VERSION 5.7 ;
  NOWIREEXTENSIONATPIN ON ;
  DIVIDERCHAR "/" ;
  BUSBITCHARS "[]" ;
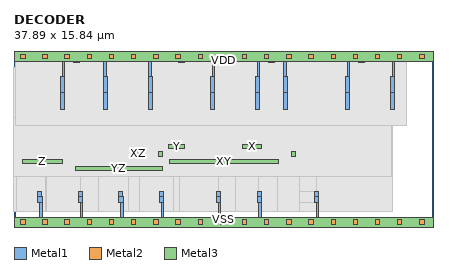
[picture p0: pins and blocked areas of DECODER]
MACRO DECODER
  CLASS BLOCK ;
  FOREIGN DECODER ;
  ORIGIN 1.000 0.000 ;
  SIZE 37.890 BY 15.840 ;
  PIN VSS
    DIRECTION INOUT ;
    USE GROUND ;
    PORT
      LAYER Metal1 ;
        RECT 1.140 2.730 1.500 3.230 ;
        RECT 4.800 2.730 5.160 3.230 ;
        RECT 8.460 2.730 8.820 3.230 ;
        RECT 12.120 2.730 12.480 3.230 ;
        RECT 17.280 2.730 17.640 3.230 ;
        RECT 20.940 2.730 21.300 3.230 ;
        RECT 26.100 2.730 26.460 3.230 ;
        RECT 1.140 2.230 1.530 2.730 ;
        RECT 4.800 2.230 5.190 2.730 ;
        RECT 8.460 2.230 8.850 2.730 ;
        RECT 12.120 2.230 12.510 2.730 ;
        RECT 17.280 2.230 17.670 2.730 ;
        RECT 20.940 2.230 21.330 2.730 ;
        RECT 26.100 2.230 26.490 2.730 ;
        RECT 1.300 0.900 1.530 2.230 ;
        RECT 4.960 0.900 5.190 2.230 ;
        RECT 8.620 0.900 8.850 2.230 ;
        RECT 12.280 0.900 12.510 2.230 ;
        RECT 17.440 0.900 17.670 2.230 ;
        RECT 21.100 0.900 21.330 2.230 ;
        RECT 26.260 0.900 26.490 2.230 ;
        RECT -1.000 0.000 36.890 0.900 ;
      LAYER Metal2 ;
        RECT -0.400 0.250 0.000 0.650 ;
        RECT 1.600 0.250 2.000 0.650 ;
        RECT 3.600 0.250 4.000 0.650 ;
        RECT 5.600 0.250 6.000 0.650 ;
        RECT 7.600 0.250 8.000 0.650 ;
        RECT 9.600 0.250 10.000 0.650 ;
        RECT 11.600 0.250 12.000 0.650 ;
        RECT 13.600 0.250 14.000 0.650 ;
        RECT 15.600 0.250 16.000 0.650 ;
        RECT 17.600 0.250 18.000 0.650 ;
        RECT 19.600 0.250 20.000 0.650 ;
        RECT 21.600 0.250 22.000 0.650 ;
        RECT 23.600 0.250 24.000 0.650 ;
        RECT 25.600 0.250 26.000 0.650 ;
        RECT 27.600 0.250 28.000 0.650 ;
        RECT 29.600 0.250 30.000 0.650 ;
        RECT 31.600 0.250 32.000 0.650 ;
        RECT 33.600 0.250 34.000 0.650 ;
        RECT 35.600 0.250 36.000 0.650 ;
      LAYER Metal3 ;
        RECT -1.000 0.000 36.890 0.900 ;
    END
  END VSS
  PIN VDD
    DIRECTION INOUT ;
    USE POWER ;
    PORT
      LAYER Metal1 ;
        RECT -1.000 14.940 36.890 15.840 ;
        RECT 3.360 13.610 3.590 14.940 ;
        RECT 4.410 14.840 4.890 14.940 ;
        RECT 3.200 12.110 3.590 13.610 ;
        RECT 7.080 13.610 7.310 14.940 ;
        RECT 11.140 13.610 11.370 14.940 ;
        RECT 13.880 14.840 14.360 14.940 ;
        RECT 16.890 13.610 17.120 14.940 ;
        RECT 20.950 13.610 21.180 14.940 ;
        RECT 22.000 14.840 22.480 14.940 ;
        RECT 7.080 12.110 7.470 13.610 ;
        RECT 11.140 12.110 11.530 13.610 ;
        RECT 3.200 10.610 3.560 12.110 ;
        RECT 7.110 10.610 7.470 12.110 ;
        RECT 11.170 10.610 11.530 12.110 ;
        RECT 16.730 12.110 17.120 13.610 ;
        RECT 20.790 12.110 21.180 13.610 ;
        RECT 23.320 13.610 23.550 14.940 ;
        RECT 29.070 13.610 29.300 14.940 ;
        RECT 30.120 14.840 30.600 14.940 ;
        RECT 33.130 13.610 33.360 14.940 ;
        RECT 23.320 12.110 23.710 13.610 ;
        RECT 16.730 10.610 17.090 12.110 ;
        RECT 20.790 10.610 21.150 12.110 ;
        RECT 23.350 10.610 23.710 12.110 ;
        RECT 28.910 12.110 29.300 13.610 ;
        RECT 32.970 12.110 33.360 13.610 ;
        RECT 28.910 10.610 29.270 12.110 ;
        RECT 32.970 10.610 33.330 12.110 ;
      LAYER Metal2 ;
        RECT -0.400 15.190 0.000 15.590 ;
        RECT 1.600 15.190 2.000 15.590 ;
        RECT 3.600 15.190 4.000 15.590 ;
        RECT 5.600 15.190 6.000 15.590 ;
        RECT 7.600 15.190 8.000 15.590 ;
        RECT 9.600 15.190 10.000 15.590 ;
        RECT 11.600 15.190 12.000 15.590 ;
        RECT 13.600 15.190 14.000 15.590 ;
        RECT 15.600 15.190 16.000 15.590 ;
        RECT 17.600 15.190 18.000 15.590 ;
        RECT 19.600 15.190 20.000 15.590 ;
        RECT 21.600 15.190 22.000 15.590 ;
        RECT 23.600 15.190 24.000 15.590 ;
        RECT 25.600 15.190 26.000 15.590 ;
        RECT 27.600 15.190 28.000 15.590 ;
        RECT 29.600 15.190 30.000 15.590 ;
        RECT 31.600 15.190 32.000 15.590 ;
        RECT 33.600 15.190 34.000 15.590 ;
        RECT 35.600 15.190 36.000 15.590 ;
      LAYER Metal3 ;
        RECT -1.000 14.940 36.890 15.840 ;
    END
  END VDD
  PIN YZ
    DIRECTION INPUT ;
    ANTENNAGATEAREA 8.000000 ;
    PORT
      LAYER Metal3 ;
      RECT 4.570 5.070 12.370 5.470 ;
    END
  END YZ
  PIN Z
    DIRECTION INOUT ;
    ANTENNADIFFAREA 2.200000 ;
    PORT
      LAYER Metal3 ;
      RECT -0.200 5.730 3.400 6.130 ;
    END
  END Z
  PIN XY
    DIRECTION INPUT ;
    ANTENNAGATEAREA 8.000000 ;
    PORT
      LAYER Metal3 ;
      RECT 13.005 5.730 22.905 6.130 ;
    END
  END XY
  PIN XZ
    DIRECTION INPUT ;
    ANTENNAGATEAREA 8.000000 ;
    PORT
      LAYER Metal3 ;
      RECT 10.030 6.390 10.430 6.790 ;
      RECT 12.030 6.390 12.430 6.790 ;
      RECT 24.030 6.390 24.430 6.790 ;
    END
  END XZ
  PIN Y
    DIRECTION INOUT ;
    ANTENNADIFFAREA 1.760000 ;
    PORT
      LAYER Metal3 ;
      RECT 12.925 7.050 14.425 7.450 ;
    END
  END Y
  PIN X
    DIRECTION INOUT ;
    ANTENNADIFFAREA 1.760000 ;
    PORT
      LAYER Metal3 ;
      RECT 19.625 7.050 21.325 7.450 ;
    END
  END X
  OBS
      LAYER Via1 ;
        RECT 15.980 1.420 17.440 2.240 ;
        RECT 24.800 1.420 26.260 2.240 ;
        RECT 1.900 13.600 3.360 14.420 ;
        RECT -1.055 1.420 33.130 14.420 ;
      LAYER Via2 ;
        RECT -1.055 4.580 33.080 9.910 ;
      LAYER Metal1 ;
        RECT 15.980 1.420 17.440 2.240 ;
        RECT 24.800 1.420 26.260 2.240 ;
        RECT 24.800 3.220 26.260 6.330 ;
        RECT 22.785 1.420 24.760 8.310 ;
        RECT 1.900 1.420 4.960 10.620 ;
        RECT -0.775 1.420 1.860 14.420 ;
        RECT 1.900 13.600 3.360 14.420 ;
        RECT 6.590 1.420 9.285 14.420 ;
        RECT 10.305 1.420 13.345 14.420 ;
        RECT 13.965 1.420 17.440 14.420 ;
        RECT 18.975 1.420 21.100 14.420 ;
        RECT 23.550 6.850 25.525 14.420 ;
        RECT 27.095 5.530 29.070 14.420 ;
        RECT 31.155 6.190 33.130 14.420 ;
      LAYER Metal2 ;
        RECT -1.055 4.580 33.080 9.910 ;
      LAYER Nwell ;
        RECT -0.900 9.130 34.430 15.840 ;
  END
END DECODER
